One B-rep face of a CAD part: STEP entity #1026.
In plain terms, the planar face has unit normal (0, -1, 0).
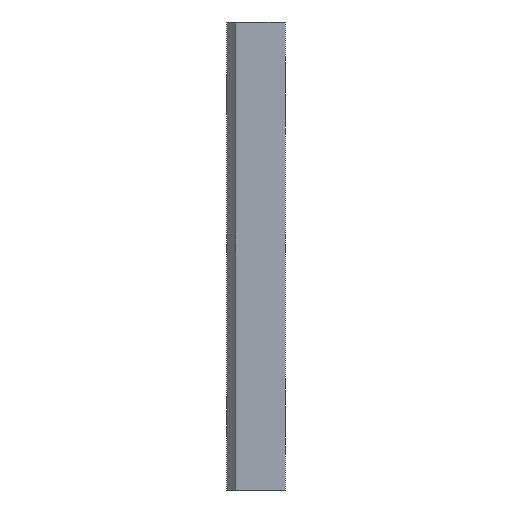
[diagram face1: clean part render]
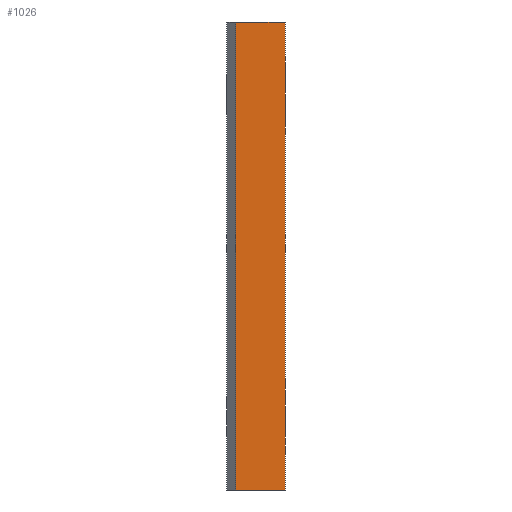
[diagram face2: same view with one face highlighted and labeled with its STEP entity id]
Its self-contained STEP definition (entity closure, numbers rounded to 3 decimals):
#450=CARTESIAN_POINT('Vertex',(20.,0.,-80.)) ;
#453=CARTESIAN_POINT('Line Origine',(11.5,0.,-80.)) ;
#457=CARTESIAN_POINT('Vertex',(3.,0.,-80.)) ;
#480=CARTESIAN_POINT('Line Origine',(3.,0.,0.)) ;
#484=CARTESIAN_POINT('Vertex',(3.,0.,80.)) ;
#504=CARTESIAN_POINT('Line Origine',(11.5,0.,80.)) ;
#508=CARTESIAN_POINT('Vertex',(20.,0.,80.)) ;
#867=CARTESIAN_POINT('Line Origine',(20.,0.,0.)) ;
#1015=CARTESIAN_POINT('Axis2P3D Location',(3.,0.,80.)) ;
#454=DIRECTION('Vector Direction',(1.,0.,0.)) ;
#481=DIRECTION('Vector Direction',(0.,0.,-1.)) ;
#505=DIRECTION('Vector Direction',(1.,0.,0.)) ;
#868=DIRECTION('Vector Direction',(0.,0.,-1.)) ;
#1016=DIRECTION('Axis2P3D Direction',(0.,1.,0.)) ;
#1017=DIRECTION('Axis2P3D XDirection',(0.,-0.,1.)) ;
#1018=AXIS2_PLACEMENT_3D('Plane Axis2P3D',#1015,#1016,#1017) ;
#1021=ORIENTED_EDGE('',*,*,#459,.T.) ;
#1022=ORIENTED_EDGE('',*,*,#871,.F.) ;
#1023=ORIENTED_EDGE('',*,*,#510,.F.) ;
#1024=ORIENTED_EDGE('',*,*,#486,.T.) ;
#455=VECTOR('Line Direction',#454,1.) ;
#482=VECTOR('Line Direction',#481,1.) ;
#506=VECTOR('Line Direction',#505,1.) ;
#869=VECTOR('Line Direction',#868,1.) ;
#1026=ADVANCED_FACE('A915-160X315',(#1025),#1019,.F.) ;
#459=EDGE_CURVE('',#458,#451,#456,.T.) ;
#486=EDGE_CURVE('',#485,#458,#483,.T.) ;
#510=EDGE_CURVE('',#485,#509,#507,.T.) ;
#871=EDGE_CURVE('',#509,#451,#870,.T.) ;
#1020=EDGE_LOOP('',(#1021,#1022,#1023,#1024)) ;
#1025=FACE_OUTER_BOUND('',#1020,.T.) ;
#456=LINE('Line',#453,#455) ;
#483=LINE('Line',#480,#482) ;
#507=LINE('Line',#504,#506) ;
#870=LINE('Line',#867,#869) ;
#1019=PLANE('Plane',#1018) ;
#451=VERTEX_POINT('',#450) ;
#458=VERTEX_POINT('',#457) ;
#485=VERTEX_POINT('',#484) ;
#509=VERTEX_POINT('',#508) ;
